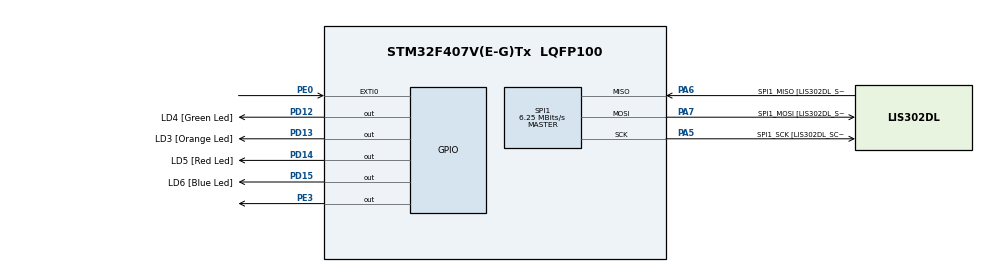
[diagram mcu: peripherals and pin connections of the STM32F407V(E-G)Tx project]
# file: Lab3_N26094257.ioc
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Mcu.Family=STM32F4
Mcu.Name=STM32F407V(E-G)Tx
Mcu.Package=LQFP100
NVIC.EXTI0_IRQn=true\:5\:0\:true\:false\:true\:true\:true\:true
NVIC.PriorityGroup=NVIC_PRIORITYGROUP_4
NVIC.TIM7_IRQn=true\:15\:0\:false\:false\:true\:false\:true\:true
NVIC.TimeBase=TIM7_IRQn
NVIC.TimeBaseIP=TIM7
PA13.Mode=Serial_Wire
PA13.Signal=SYS_JTMS-SWDIO
PA14.Mode=Serial_Wire
PA14.Signal=SYS_JTCK-SWCLK
PA5.GPIO_Label=SPI1_SCK [LIS302DL_SCL/SPC]
PA5.GPIO_Mode=GPIO_MODE_AF_PP
PA5.GPIO_PuPd=GPIO_NOPULL
PA5.GPIO_Speed=GPIO_SPEED_FREQ_LOW
PA5.Mode=Full_Duplex_Master
PA5.Signal=SPI1_SCK
PA6.GPIO_Label=SPI1_MISO [LIS302DL_SDO]
PA6.GPIO_Mode=GPIO_MODE_AF_PP
PA6.GPIO_PuPd=GPIO_NOPULL
PA6.GPIO_Speed=GPIO_SPEED_FREQ_LOW
PA6.Mode=Full_Duplex_Master
PA6.Signal=SPI1_MISO
PA7.GPIO_Label=SPI1_MOSI [LIS302DL_SDA/SDI/SDO]
PA7.GPIO_Mode=GPIO_MODE_AF_PP
PA7.GPIO_PuPd=GPIO_NOPULL
PA7.GPIO_Speed=GPIO_SPEED_FREQ_LOW
PA7.Mode=Full_Duplex_Master
PA7.Signal=SPI1_MOSI
PD12.GPIO_Label=LD4 [Green Led]
PD12.GPIO_PuPd=GPIO_NOPULL
PD12.GPIO_Speed=GPIO_SPEED_FREQ_LOW
PD12.Signal=GPIO_Output
PD13.GPIO_Label=LD3 [Orange Led]
PD13.GPIO_PuPd=GPIO_NOPULL
PD13.GPIO_Speed=GPIO_SPEED_FREQ_LOW
PD13.Signal=GPIO_Output
PD14.GPIO_Label=LD5 [Red Led]
PD14.GPIO_PuPd=GPIO_NOPULL
PD14.GPIO_Speed=GPIO_SPEED_FREQ_LOW
PD14.Signal=GPIO_Output
PD15.GPIO_Label=LD6 [Blue Led]
PD15.GPIO_PuPd=GPIO_NOPULL
PD15.GPIO_Speed=GPIO_SPEED_FREQ_LOW
PD15.Signal=GPIO_Output
PE0.Signal=GPXTI0
PE3.Signal=GPIO_Output
ProjectManager.HeapSize=0x200
ProjectManager.StackSize=0x400
ProjectManager.TargetToolchain=STM32CubeIDE
RCC.48MHZClocksFreq_Value=14285714.285714285
RCC.AHBFreq_Value=25000000
RCC.APB1CLKDivider=RCC_HCLK_DIV4
RCC.APB1Freq_Value=6250000
RCC.APB1TimFreq_Value=12500000
RCC.APB2CLKDivider=RCC_HCLK_DIV2
RCC.APB2Freq_Value=12500000
RCC.APB2TimFreq_Value=25000000
RCC.CortexFreq_Value=25000000
RCC.HCLKFreq_Value=25000000
RCC.HSE_VALUE=8000000
RCC.HSI_VALUE=16000000
RCC.LSE_VALUE=32768
RCC.PLLM=8
RCC.PLLN=50
RCC.PLLP=RCC_PLLP_DIV4
RCC.PLLQ=7
RCC.SYSCLKFreq_VALUE=25000000
RCC.SYSCLKSource=RCC_SYSCLKSOURCE_PLLCLK
RCC.VCOOutputFreq_Value=100000000
SPI1.CalculateBaudRate=6.25 MBits/s
SPI1.Direction=SPI_DIRECTION_2LINES
SPI1.Mode=SPI_MODE_MASTER
SPI1.VirtualType=VM_MASTER
VP_SYS_VS_tim7.Mode=TIM7
board=STM32F407G-DISC1

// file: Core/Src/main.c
/* USER CODE BEGIN Header */
/**
  ******************************************************************************
  * @file           : main.c
  * @brief          : Main program body
  ******************************************************************************
  * @attention
  *
  * <h2><center>&copy; Copyright (c) 2021 STMicroelectronics.
  * All rights reserved.</center></h2>
  *
  * This software component is licensed by ST under BSD 3-Clause license,
  * the "License"; You may not use this file except in compliance with the
  * License. You may obtain a copy of the License at:
  *                        opensource.org/licenses/BSD-3-Clause
  *
  ******************************************************************************
  */
/* USER CODE END Header */
#include "main.h"

/* USER CODE BEGIN Includes */
#include "FreeRTOS.h"
#include "task.h"
#include "semphr.h"
/* USER CODE END Includes */

/* USER CODE BEGIN PM */
#define LIS3DSH_WHO_AM_I_ADDR                0x0F
#define LIS3DSH_STAT_ADDR                    0x18
#define LIS3DSH_CTRL_REG4_ADDR               0x20
#define LIS3DSH_CTRL_REG1_ADDR               0x21
#define LIS3DSH_CTRL_REG2_ADDR               0x22
#define LIS3DSH_CTRL_REG3_ADDR               0x23
#define LIS3DSH_CTRL_REG5_ADDR               0x24
#define LIS3DSH_CTRL_REG6_ADDR               0x25

#define LIS3DSH_STATUS_ADDR                  0x27

#define LIS3DSH_OUT_X_L_ADDR                 0x28
#define LIS3DSH_OUT_X_H_ADDR                 0x29
#define LIS3DSH_OUT_Y_L_ADDR                 0x2A
#define LIS3DSH_OUT_Y_H_ADDR                 0x2B
#define LIS3DSH_OUT_Z_L_ADDR                 0x2C
#define LIS3DSH_OUT_Z_H_ADDR                 0x2D

#define LIS3DSH_ST1_1_ADDR                   0x40
#define LIS3DSH_ST1_2_ADDR                   0x41
#define LIS3DSH_THRS1_1_ADDR                 0x57
#define LIS3DSH_MASK1_B_ADDR                 0x59
#define LIS3DSH_MASK1_A_ADDR                 0x5A
#define LIS3DSH_SETT1_ADDR                   0x5B
/* USER CODE END PM */

SPI_HandleTypeDef hspi1;

void SystemClock_Config(void);
static void MX_GPIO_Init(void);
static void MX_SPI1_Init(void);

/* USER CODE BEGIN 0 */
uint8_t state = 0;
SemaphoreHandle_t xSemaphore;
void Green_Task(void *pvParameters);
void Handler_Task(void *pvParameters);

void MEMS_Write(uint8_t address,uint8_t data){
	HAL_GPIO_WritePin(GPIOE, GPIO_PIN_3, GPIO_PIN_RESET);
	HAL_SPI_Transmit(&hspi1,&address,1,10);
	HAL_SPI_Transmit(&hspi1,&data,1,10);
	HAL_GPIO_WritePin(GPIOE, GPIO_PIN_3,GPIO_PIN_SET);
}

void MEMS_Read(uint8_t address,uint8_t *data){
    address |= 0x80;
	HAL_GPIO_WritePin(GPIOE,GPIO_PIN_3,GPIO_PIN_RESET);
	HAL_SPI_Transmit(&hspi1,&address,1,10);
	HAL_SPI_Receive(&hspi1,data,1,10);
	HAL_GPIO_WritePin(GPIOE,GPIO_PIN_3,GPIO_PIN_SET);
}
/* USER CODE END 0 */

int main(void)
{

  /* MCU Configuration--------------------------------------------------------*/

  /* Reset of all peripherals, Initializes the Flash interface and the Systick. */
  HAL_Init();

  /* Configure the system clock */
  SystemClock_Config();

  /* Initialize all configured peripherals */
  MX_GPIO_Init();
  MX_SPI1_Init();
  /* USER CODE BEGIN 2 */

  // Set MEMS register value
  MEMS_Write(LIS3DSH_CTRL_REG1_ADDR, 0x01);
  MEMS_Write(LIS3DSH_CTRL_REG3_ADDR, 0x48);
  MEMS_Write(LIS3DSH_CTRL_REG4_ADDR, 0x67);
  MEMS_Write(LIS3DSH_CTRL_REG5_ADDR, 0x00);
  MEMS_Write(LIS3DSH_THRS1_1_ADDR, 0x55);
  MEMS_Write(LIS3DSH_ST1_1_ADDR, 0x05);
  MEMS_Write(LIS3DSH_ST1_2_ADDR, 0x11);
  MEMS_Write(LIS3DSH_MASK1_B_ADDR, 0xFC);
  MEMS_Write(LIS3DSH_MASK1_A_ADDR, 0xFC);
  MEMS_Write(LIS3DSH_SETT1_ADDR, 0x1);

  /* USER CODE END 2 */

  // Create semaphore

  xSemaphore=xSemaphoreCreateBinary();
  // Create two tasks
  xTaskCreate(Green_Task, "Green", 1000, NULL, 1, NULL);
  xTaskCreate(Handler_Task, "Handler", 1000, NULL, 3, NULL);

  // Start the scheduler
  vTaskStartScheduler();

  /* Infinite loop */
  while (1)
  {

  }
}

void SystemClock_Config(void)
{
  RCC_OscInitTypeDef RCC_OscInitStruct = {0};
  RCC_ClkInitTypeDef RCC_ClkInitStruct = {0};

  /** Configure the main internal regulator output voltage
  */
  __HAL_RCC_PWR_CLK_ENABLE();
  __HAL_PWR_VOLTAGESCALING_CONFIG(PWR_REGULATOR_VOLTAGE_SCALE1);
  /** Initializes the RCC Oscillators according to the specified parameters
  * in the RCC_OscInitTypeDef structure.
  */
  RCC_OscInitStruct.OscillatorType = RCC_OSCILLATORTYPE_HSI;
  RCC_OscInitStruct.HSIState = RCC_HSI_ON;
  RCC_OscInitStruct.HSICalibrationValue = RCC_HSICALIBRATION_DEFAULT;
  RCC_OscInitStruct.PLL.PLLState = RCC_PLL_NONE;
  if (HAL_RCC_OscConfig(&RCC_OscInitStruct) != HAL_OK)
  {
    Error_Handler();
  }
  /** Initializes the CPU, AHB and APB buses clocks
  */
  RCC_ClkInitStruct.ClockType = RCC_CLOCKTYPE_HCLK|RCC_CLOCKTYPE_SYSCLK
                              |RCC_CLOCKTYPE_PCLK1|RCC_CLOCKTYPE_PCLK2;
  RCC_ClkInitStruct.SYSCLKSource = RCC_SYSCLKSOURCE_HSI;
  RCC_ClkInitStruct.AHBCLKDivider = RCC_SYSCLK_DIV1;
  RCC_ClkInitStruct.APB1CLKDivider = RCC_HCLK_DIV1;
  RCC_ClkInitStruct.APB2CLKDivider = RCC_HCLK_DIV1;

  if (HAL_RCC_ClockConfig(&RCC_ClkInitStruct, FLASH_LATENCY_0) != HAL_OK)
  {
    Error_Handler();
  }
}

static void MX_SPI1_Init(void)
{

  /* SPI1 parameter configuration*/
  hspi1.Instance = SPI1;
  hspi1.Init.Mode = SPI_MODE_MASTER;
  hspi1.Init.Direction = SPI_DIRECTION_2LINES;
  hspi1.Init.DataSize = SPI_DATASIZE_8BIT;
  hspi1.Init.CLKPolarity = SPI_POLARITY_LOW;
  hspi1.Init.CLKPhase = SPI_PHASE_1EDGE;
  hspi1.Init.NSS = SPI_NSS_SOFT;
  hspi1.Init.BaudRatePrescaler = SPI_BAUDRATEPRESCALER_2;
  hspi1.Init.FirstBit = SPI_FIRSTBIT_MSB;
  hspi1.Init.TIMode = SPI_TIMODE_DISABLE;
  hspi1.Init.CRCCalculation = SPI_CRCCALCULATION_DISABLE;
  hspi1.Init.CRCPolynomial = 10;
  if (HAL_SPI_Init(&hspi1) != HAL_OK)
  {
    Error_Handler();
  }

}

static void MX_GPIO_Init(void)
{
  GPIO_InitTypeDef GPIO_InitStruct = {0};

  /* GPIO Ports Clock Enable */
  __HAL_RCC_GPIOE_CLK_ENABLE();
  __HAL_RCC_GPIOA_CLK_ENABLE();
  __HAL_RCC_GPIOD_CLK_ENABLE();

  /*Configure GPIO pin Output Level */
  HAL_GPIO_WritePin(GPIOE, GPIO_PIN_3, GPIO_PIN_RESET);

  /*Configure GPIO pin Output Level */
  HAL_GPIO_WritePin(GPIOD, GPIO_PIN_12|GPIO_PIN_13|GPIO_PIN_14, GPIO_PIN_RESET);

  /*Configure GPIO pin : PE3 */
  GPIO_InitStruct.Pin = GPIO_PIN_3;
  GPIO_InitStruct.Mode = GPIO_MODE_OUTPUT_PP;
  GPIO_InitStruct.Pull = GPIO_NOPULL;
  GPIO_InitStruct.Speed = GPIO_SPEED_FREQ_LOW;
  HAL_GPIO_Init(GPIOE, &GPIO_InitStruct);

  /*Configure GPIO pins : Green_LED_Pin Orange_LED_Pin Red_LED_Pin */
  GPIO_InitStruct.Pin = GPIO_PIN_12|GPIO_PIN_13|GPIO_PIN_14;
  GPIO_InitStruct.Mode = GPIO_MODE_OUTPUT_PP;
  GPIO_InitStruct.Pull = GPIO_NOPULL;
  GPIO_InitStruct.Speed = GPIO_SPEED_FREQ_LOW;
  HAL_GPIO_Init(GPIOD, &GPIO_InitStruct);

  /*Configure GPIO pin : PE0 */
  GPIO_InitStruct.Pin = GPIO_PIN_0;
  GPIO_InitStruct.Mode = GPIO_MODE_IT_RISING;
  GPIO_InitStruct.Pull = GPIO_NOPULL;
  HAL_GPIO_Init(GPIOE, &GPIO_InitStruct);

  /* EXTI interrupt init*/
  HAL_NVIC_SetPriority(EXTI0_IRQn, 6, 0);
  HAL_NVIC_EnableIRQ(EXTI0_IRQn);

}

/* USER CODE BEGIN 4 */
void HAL_GPIO_EXTI_Callback(uint16_t GPIO_Pin)
{

	/* Prevent unused argument(s) compilation warning */
	//UNUSED(GPIO_Pin);
	/* NOTE: This function Should not be modified, when the callback is needed,
		   the HAL_GPIO_EXTI_Callback could be implemented in the user file
	*/

	// Toggle red LED
	HAL_GPIO_TogglePin(GPIOD, GPIO_PIN_14);

	// Give semaphore
	BaseType_t xHigherPriorityTaskWoken;
	xHigherPriorityTaskWoken = pdFALSE;
	xSemaphoreGiveFromISR(xSemaphore, &xHigherPriorityTaskWoken);
	portYIELD_FROM_ISR(xHigherPriorityTaskWoken);

}

void Green_Task(void *pvParameters)
{
	for(;;)
	{
		if(state==0)
		{
			HAL_GPIO_TogglePin(GPIOD, GPIO_PIN_12);
			vTaskDelay(500);
		}else
		{
			HAL_GPIO_WritePin(GPIOD,GPIO_PIN_12,GPIO_PIN_RESET);
		}
	}
}

void Handler_Task(void *pvParameters)
{
	for(;;)
	{
		// Take semaphore
		if(xSemaphoreTake(xSemaphore, portMAX_DELAY)==pdTRUE)
		{
			state=1;
			// Blink orange LED 5 times
			for (int i=0; i<5; i++){
				HAL_GPIO_TogglePin(GPIOD, GPIO_PIN_13);
				vTaskDelay(250);
		}
		// Reset the interrupt register
		state=0;
		int data=0;
		MEMS_Read(0x5F, &data);
		}
	}
}

/* USER CODE END 4 */

 /**
  * @brief  Period elapsed callback in non blocking mode
  * @note   This function is called  when TIM6 interrupt took place, inside
  * HAL_TIM_IRQHandler(). It makes a direct call to HAL_IncTick() to increment
  * a global variable "uwTick" used as application time base.
  * @param  htim : TIM handle
  * @retval None
  */
void HAL_TIM_PeriodElapsedCallback(TIM_HandleTypeDef *htim)
{
  if (htim->Instance == TIM6) {
    HAL_IncTick();
  }
}

void Error_Handler(void)
{
  __disable_irq();
  while (1)
  {
  }
}

/************************ (C) COPYRIGHT STMicroelectronics *****END OF FILE****/
